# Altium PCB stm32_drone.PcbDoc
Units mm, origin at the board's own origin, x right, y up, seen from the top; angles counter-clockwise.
Board outline 76 x 62 mm, 4 copper layers (Top Layer, Int1 (GND), Int2 (PWR), Bottom Layer), stack 1.564 mm thick; 44 components, 39 nets, 236 pads, 228 vias.
Unrouted connection lines stored in the file: 6.

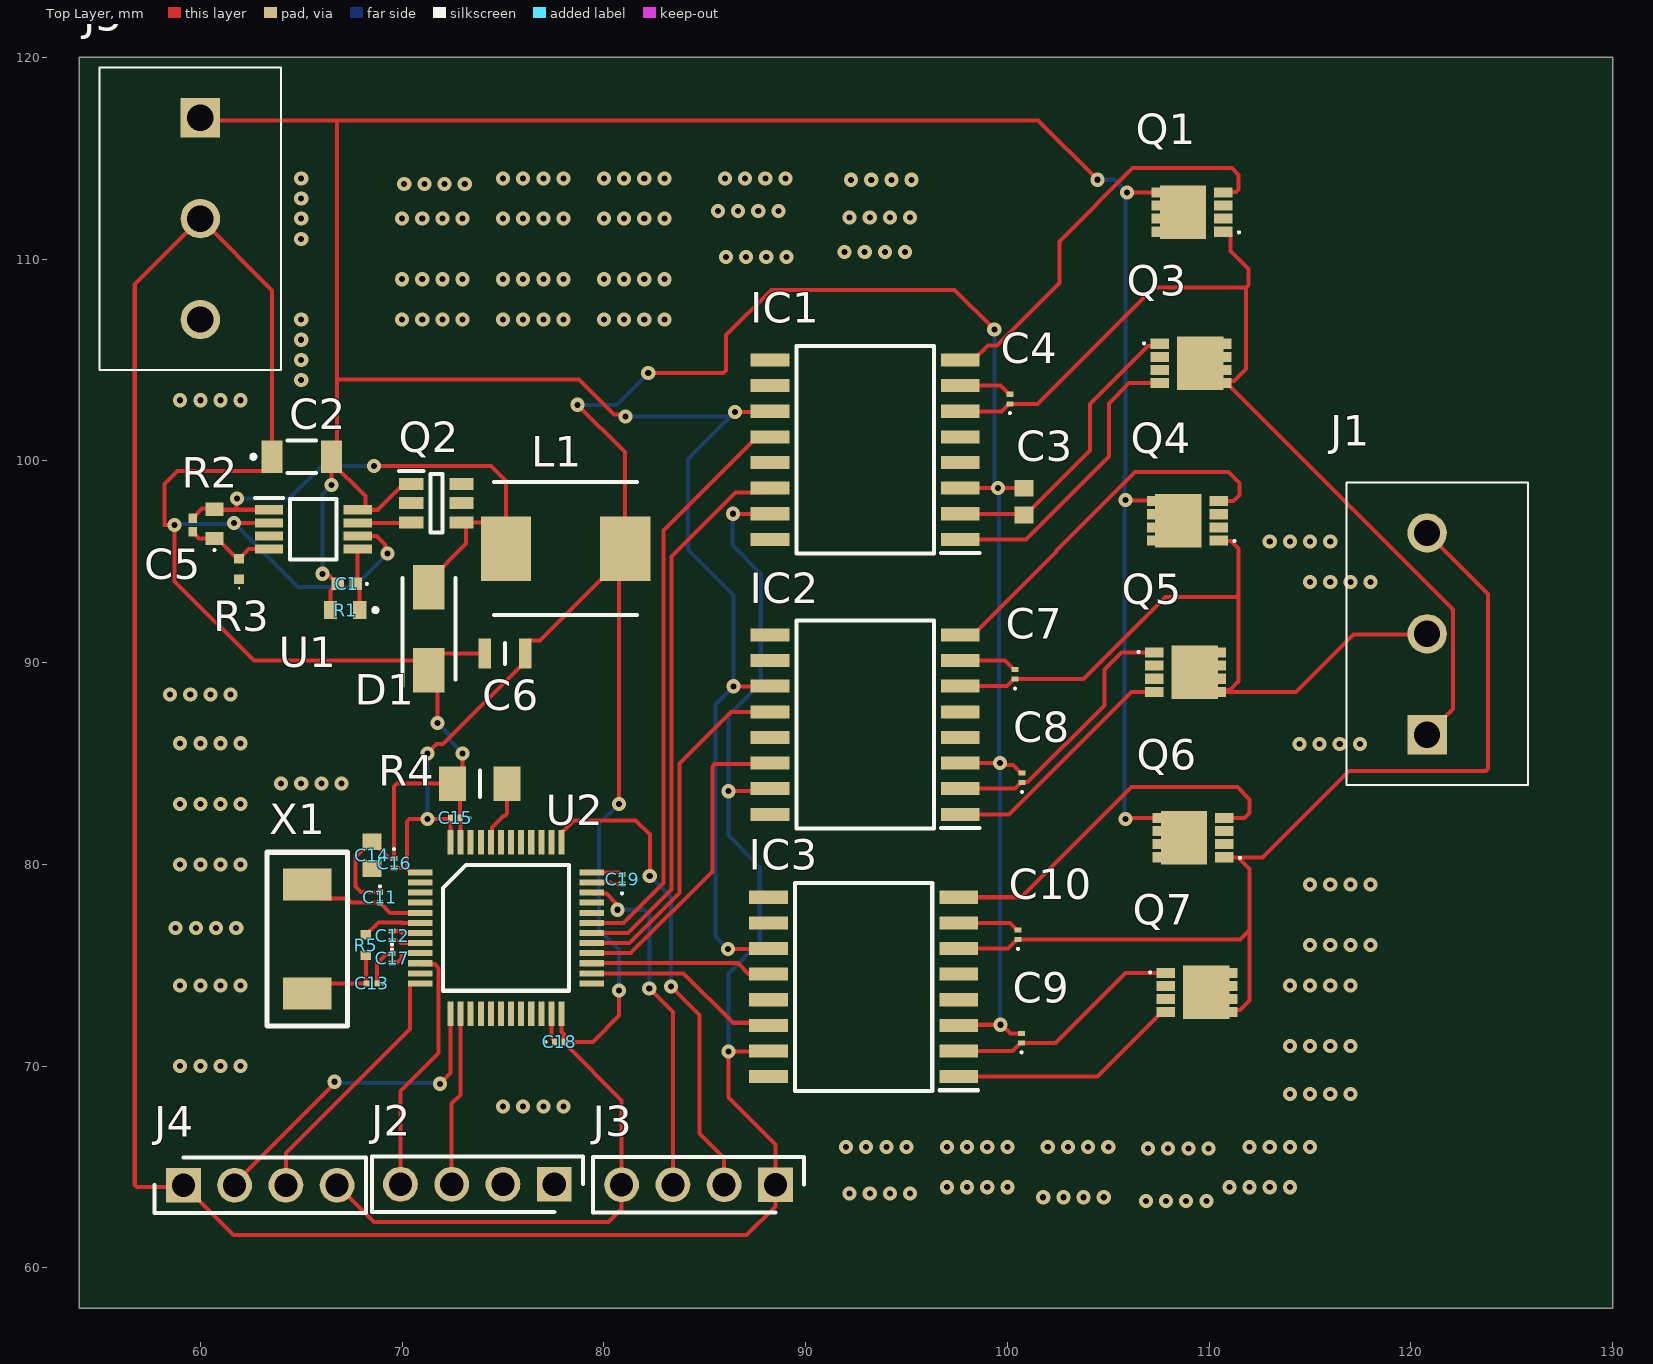
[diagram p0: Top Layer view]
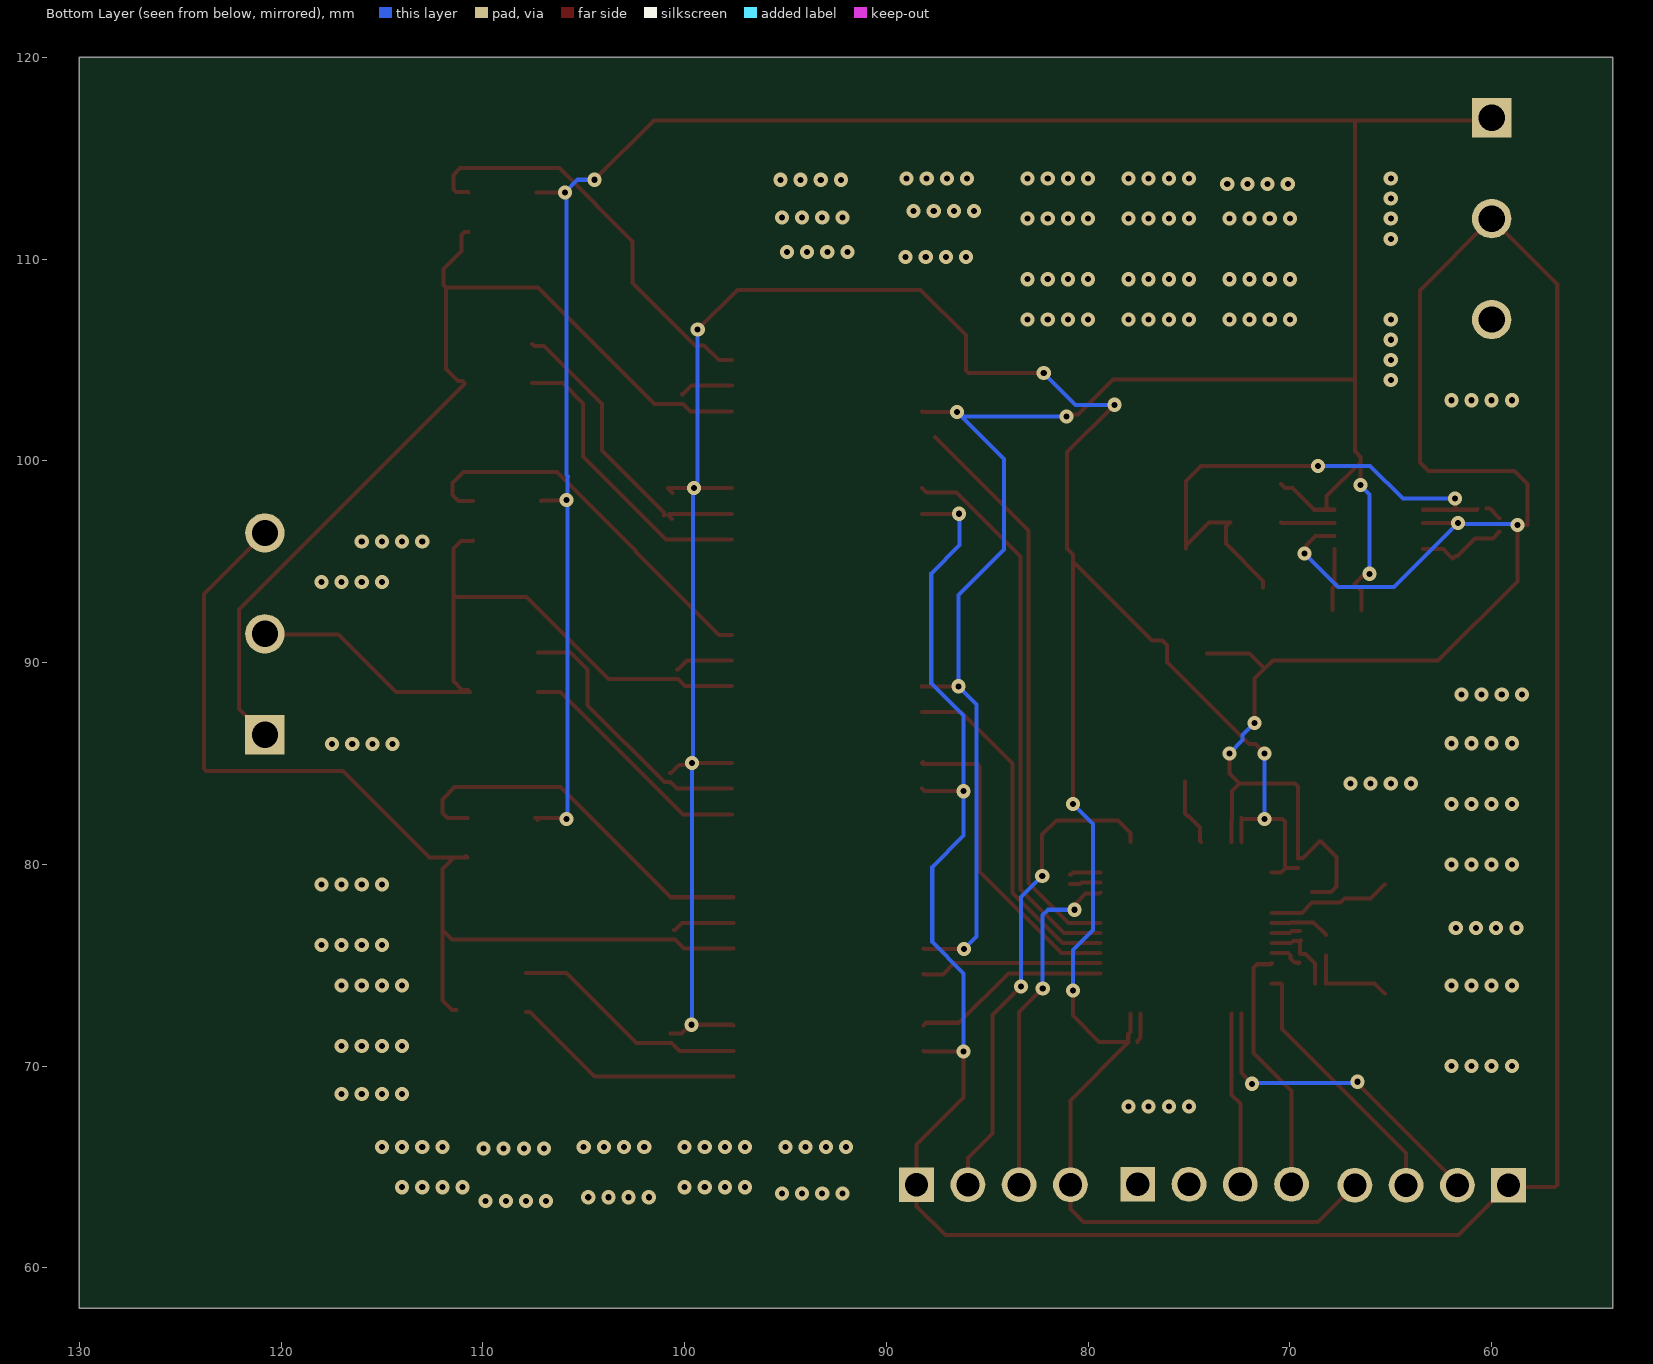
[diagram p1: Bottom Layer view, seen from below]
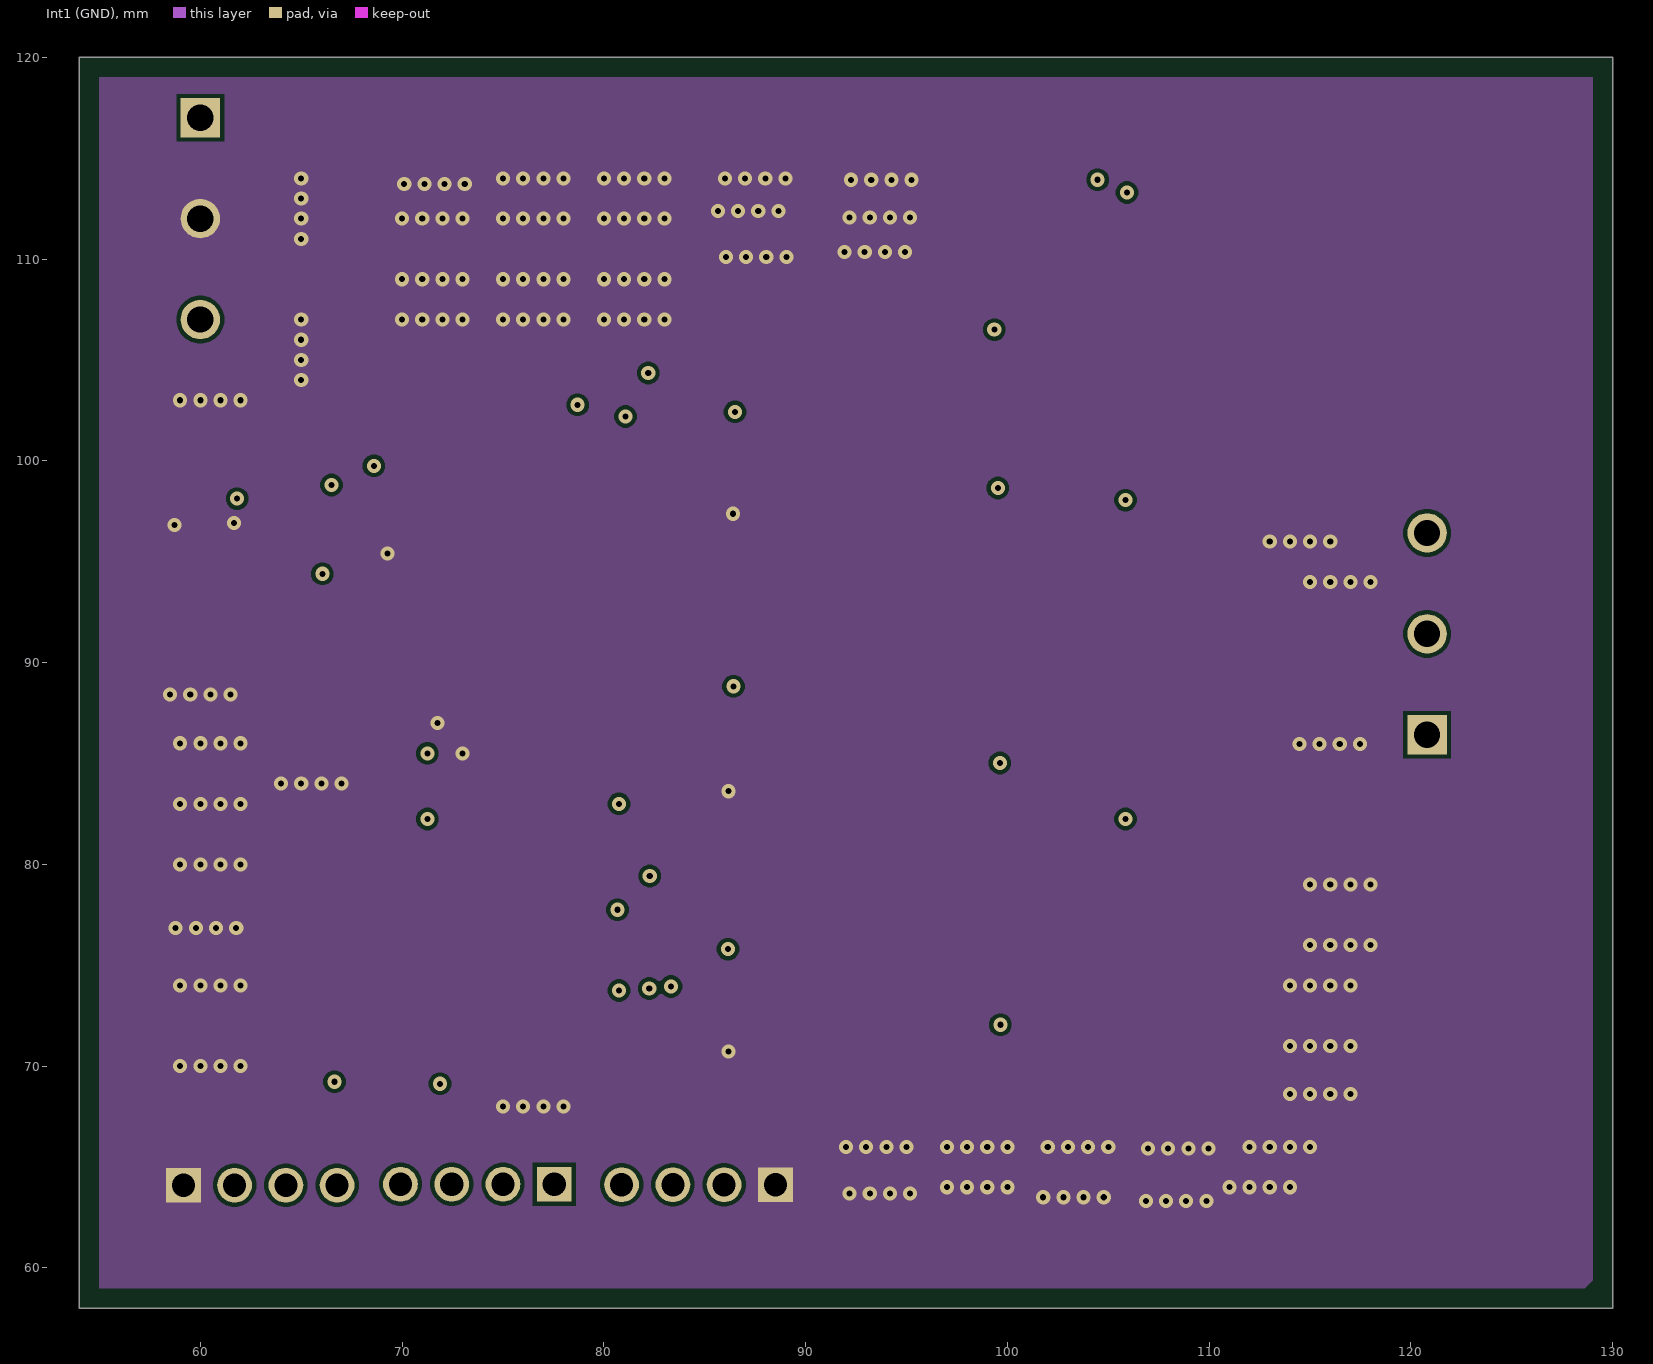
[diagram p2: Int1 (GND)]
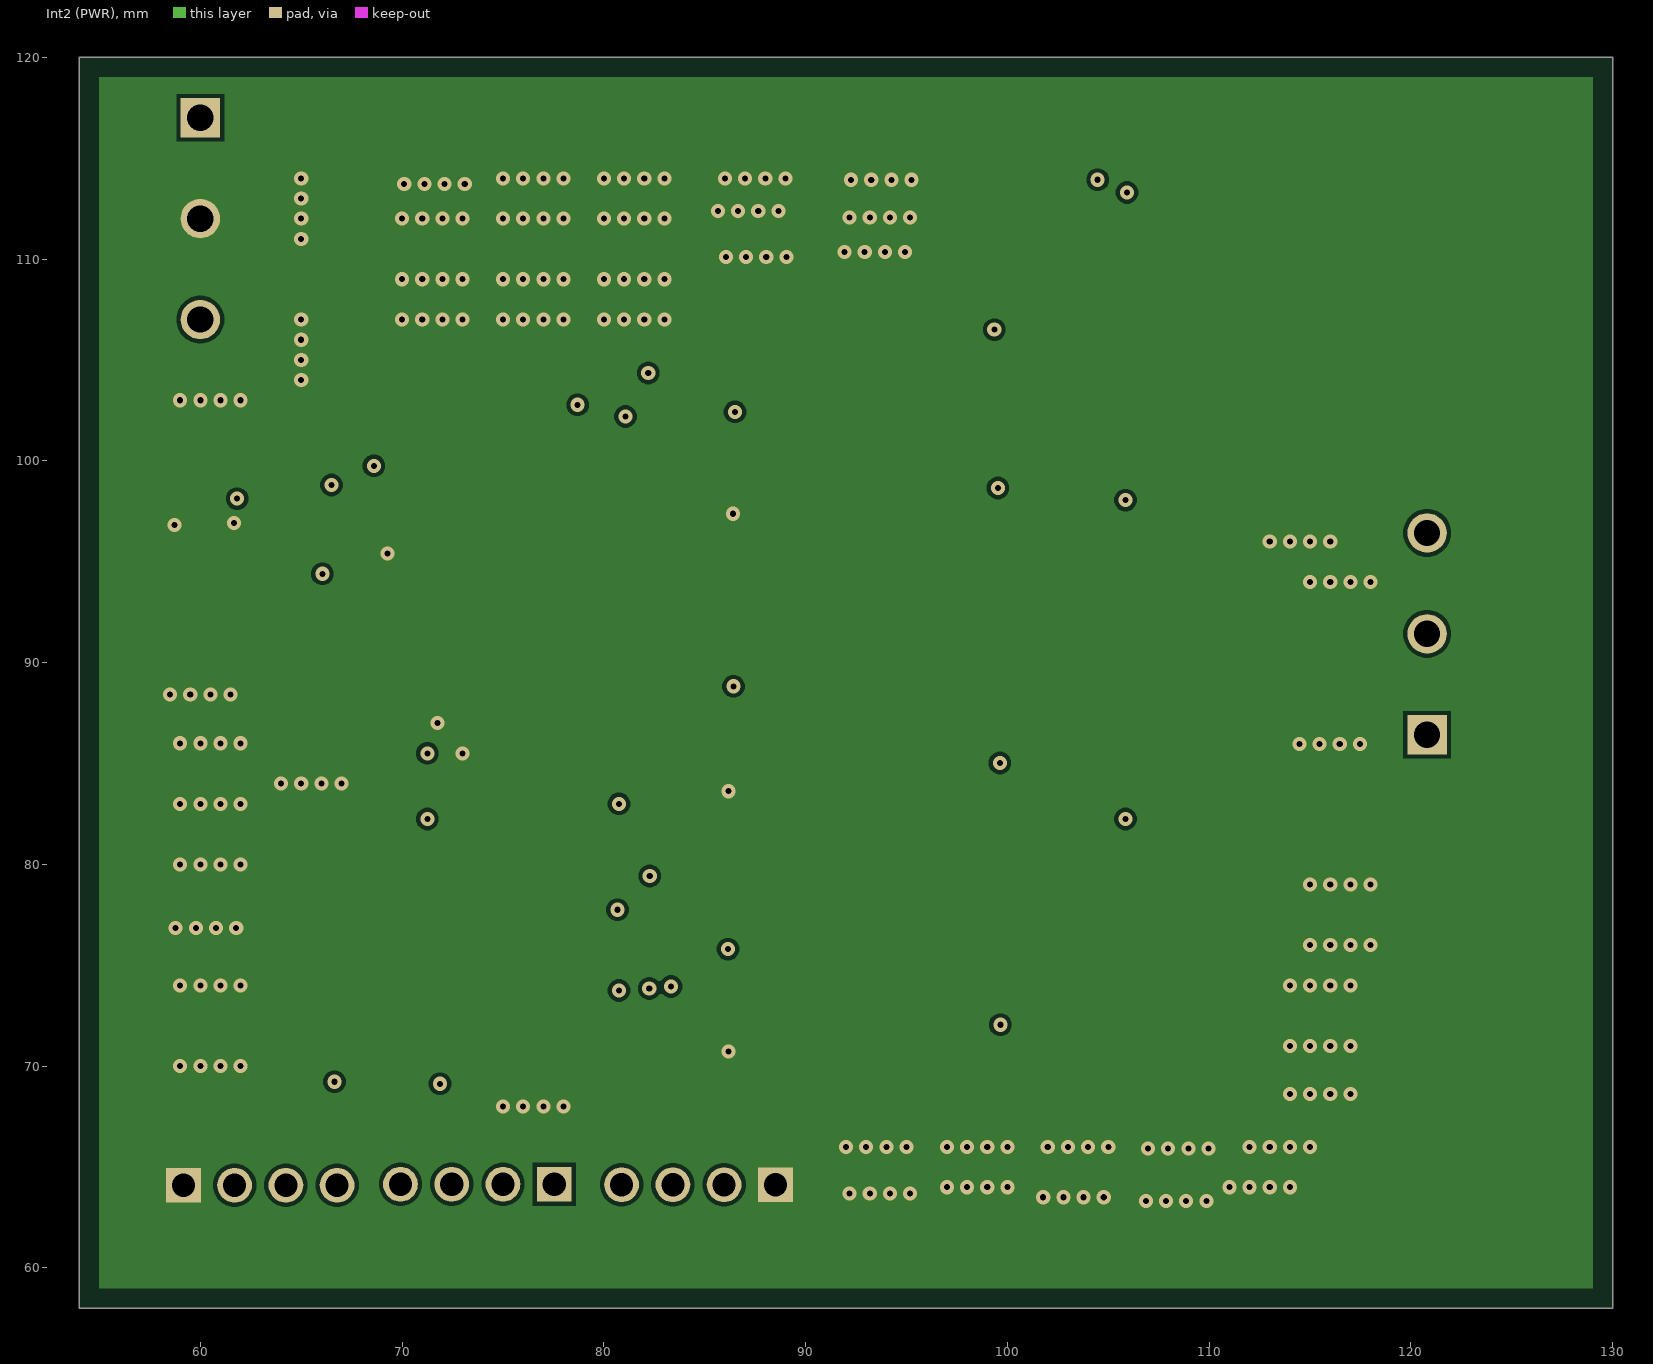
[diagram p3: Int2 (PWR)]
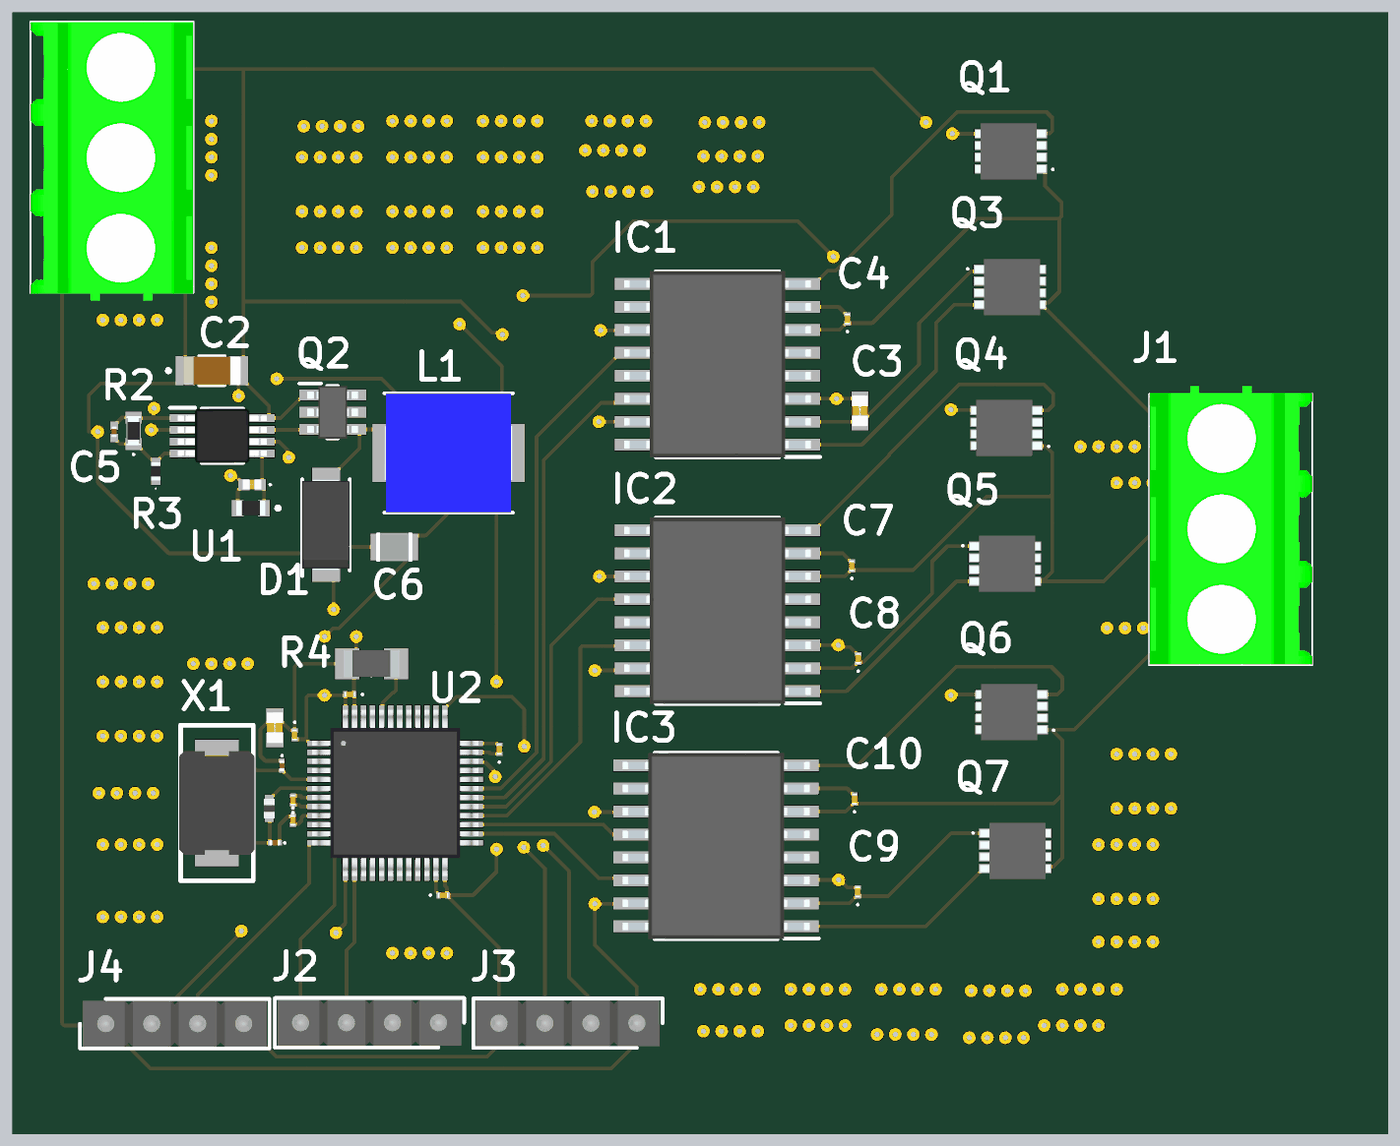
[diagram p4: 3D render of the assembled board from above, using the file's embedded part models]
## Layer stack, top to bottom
Top Solder: solder mask 0.0305, SM-001, Dk 3.8
Top Layer: signal copper 0.035
Dielectric 1: prepreg 0.0994, PP-023, Dk 4.4
Int1 (GND): signal copper 0.0152
Dielectric 3: core 1.265, Core-039, Dk 4.6
Int2 (PWR): signal copper 0.0152
Dielectric 5: prepreg 0.0994, PP-023, Dk 4.4
Bottom Layer: signal copper 0.035
Bottom Solder: solder mask 0.0305, SM-001, Dk 3.8

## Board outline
54,58 54,120 130,120 130,58

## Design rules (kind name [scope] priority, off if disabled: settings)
Clearance [All] p1: gap=0.2 ignorepadtopadclearanceinfootprint=FALSE
PolygonConnect [All] p1: connectstyle=Direct reliefconductorwidth=0.254 reliefentries=4 polygonreliefangle="90 Angle" airgapwidth=0.254
RoutingVias [All] p1: holewidth=0.5 width=0.7 viastyle="Through Hole" minholewidth=0.25 minwidth=0.55 maxholewidth=0.4 maxwidth=0.9
SolderMaskExpansion [All] p1: expansion=0.038 istentingtop=FALSE
SupplyNets "Schematic Supply Nets_1" [InNet('VDD')] p1: voltage=0.000
SupplyNets "Schematic Supply Nets_2" [InNet('3v3')] p2: voltage=0.000
SupplyNets "Schematic Supply Nets" [InNet('GND')] p3: voltage=0.000
UnRoutedNet [All] p1: checkbadconnections=TRUE
Width [All] p1: maxlimit=1 minlimit=0.16 preferedwidth=0.2
29 further rules are at their usual default settings.

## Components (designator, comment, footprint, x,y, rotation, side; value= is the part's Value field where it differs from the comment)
C1 "1nF" C0402C104J4RACTU 67.25,93.9 r180 top
C2 "100uF" GRM31x 65.025,100.2 r0 top
C3 "1uF" CAPC1608X90N 100.825,97.975 r90 top
C4 "1uF" GRM033D70J224ME01D 100.125,103.062 r90 top
C5 "100pF" CAPC0603X33N 59.625,96.82 r90 top
C6 "22uF" CAPC2012X145N 75.1,90.45 r0 top
C7 "1uF" GRM033D70J224ME01D 100.375,89.413 r90 top
C8 "1uF" GRM033D70J224ME01D 100.725,84.287 r90 top
C9 "1uF" GRM033D70J224ME01D 100.7,71.387 r90 top
C10 "1uF" GRM033D70J224ME01D 100.525,76.513 r90 top
C11 "2pF" GJM033 68.9,78.363 r270 top
C12 "100nF" GRM033D70J224ME01D 69.5,76.463 r90 top
C13 "2pF" GJM033 68.5,74.1 r180 top
C14 "1uF" CAPC1608X90N 68.5,80.46 r270 top
C15 "100nF" GRM033D70J224ME01D 72.637,82.3 r180 top
C16 "100nF" GRM033D70J224ME01D 69.6,80.063 r270 top
C17 "100nF" GRM033D70J224ME01D 69.5,75.337 r270 top
C18 "100nF" GRM033D70J224ME01D 77.8,71.2 r0 top
C19 "100nF" GRM033D70J224ME01D 80.9,79.263 r90 top
D1 "1A 40V" DIOM5026X262N 71.325,91.675 r90 top
IC1 "IR2110STRPBF" SOIC127P1032X265-16N 92.95,100.55 r180 top
IC2 "IR2110STRPBF" SOIC127P1032X265-16N 92.95,86.925 r180 top
IC3 "IR2110STRPBF" SOIC127P1032X265-16N 92.875,73.925 r180 top
J1 "1935174" 1935174 120.8,86.425 r90 top
J2 "61300411121" HDRV4W95P0X254_1X4_1016X254X854P 77.54,64.15 r180 top
J3 "61300411121" HDRV4W95P0X254_1X4_1016X254X854P 88.5,64.125 r180 top
J4 "61300411121" HDRV4W95P0X254_1X4_1016X254X854P 59.16,64.1 r0 top
J5 "1935174" 1935174 60,117 r270 top
L1 "22uH" INDPM7166X300N 78.1,95.65 r0 top
Q1 "XPN6R706NC,L1XHQ" XPN6R706NCL1XHQ 109.025,112.325 r90 top
Q2 "FDC5614P" SOT95P280X110-6N 71.7,97.9 r0 top
Q3 "XPN6R706NC,L1XHQ" XPN6R706NCL1XHQ 109.225,104.825 r270 top
Q4 "XPN6R706NC,L1XHQ" XPN6R706NCL1XHQ 108.8,97.025 r90 top
Q5 "XPN6R706NC,L1XHQ" XPN6R706NCL1XHQ 108.95,89.525 r270 top
Q6 "XPN6R706NC,L1XHQ" XPN6R706NCL1XHQ 109.075,81.325 r90 top
Q7 "XPN6R706NC,L1XHQ" XPN6R706NCL1XHQ 109.525,73.65 r270 top
R1 "240k" ERJ3EKF1000V 67.175,92.6 r180 top value=240kR
R2 "33k" ERA3AEB101V 60.7,96.875 r90 top value=33kR
R3 "20k" ERJ2RKD1004X 61.925,94.638 r90 top value=20kR
R4 "10k" RESC3115X60N 73.85,84 r0 top value=10kR
R5 "500" ERA2AED122X 68.2,76 r90 top value=499R
U1 "LM3485MMX/NOPB" SOP65P490X110-8N 65.6,96.6 r0 top
U2 "STMF103C8T6_LQFP48" STM32F103C8T6_LQFP48 75.15,76.85 r0 top
X1 "8Mhz" "8Mhz Crystal" 65.3,76.3 r90 top

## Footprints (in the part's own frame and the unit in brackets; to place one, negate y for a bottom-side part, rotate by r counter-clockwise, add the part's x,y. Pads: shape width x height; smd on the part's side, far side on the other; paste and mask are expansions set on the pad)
"8Mhz Crystal" [mm]
  rect 1.6x2.4 smd: 1(-2.7,0) 2(2.7,0)
  silkscreen extent -4.3,-2 4.3,2, body extent -2.86,-2.09 2.86,2.09, height 1.09
1935174 [mm]
  rect 1.95x1.95 hole 1.3: 1(0,0)
  round 1.95 hole 1.3: 2(5,0) 3(10,0)
  silkscreen extent -2.5,-5 12.5,4, body extent -2.47,-5 12.93,4, height 11.63
C0402C104J4RACTU [mm]
  rect 0.62x0.62 smd: 1(-0.45,0) 2(0.45,0)
  silkscreen extent -1.05,-0.05 -0.95,0.05, body extent -0.52,-0.28 0.53,0.27, height 0.55
CAPC0603X33N [mm]
  rect 0.46x0.42 smd: 1(-0.33,0) 2(0.33,0)
  body extent -0.3,-0.15 0.3,0.15, height 0.33
CAPC1608X90N [mm]
  rect 0.83x0.94 smd: 1(-0.66,0) 2(0.66,0)
  body extent -0.85,-0.45 0.85,0.45, height 0.9
CAPC2012X145N [mm]
  rect 0.62x1.47 smd: 1(-1,0) 2(1,0)
  silkscreen extent 0,-0.53 0,0.53, body extent -1,-0.8 1,0.8, height 1.25
DIOM5026X262N [mm]
  rect 2.2x1.55 smd: 1(-2.05,0) 2(2.05,0)
  silkscreen extent -2.83,-1.31 2.52,1.31, body extent -2.52,-1.31 2.52,1.31, height 2.62
ERA2AED122X [mm]
  rect 0.475x0.5 smd: 1(-0.512,0) 2(0.512,0)
  body extent -0.55,-0.31 0.55,0.31, height 0.41
ERA3AEB101V [mm]
  rect 0.65x0.9 smd: 1(-0.725,0) 2(0.725,0)
  silkscreen extent -1.35,-0.05 -1.25,0.05, body extent -0.8,-0.4 0.8,0.4, height 0.45
ERJ2RKD1004X [mm]
  rect 0.475x0.5 smd: 1(-0.512,0) 2(0.512,0)
  silkscreen extent -0.97,-0.03 -0.93,0.03, body extent -0.5,-0.25 0.5,0.25, height 0.35
ERJ3EKF1000V [mm]
  rect 0.65x0.9 smd: 1(-0.725,0) 2(0.725,0)
  silkscreen extent -1.6,-0.1 -1.4,0.1, body extent -0.8,-0.4 0.8,0.4, height 0.45
GJM033 [mm]
  rect 0.275x0.3 smd: 1(-0.263,0) 2(0.263,0)
  silkscreen extent -0.6,-0.05 -0.5,0.05, body extent -0.3,-0.15 0.3,0.15, height 0.33
GRM31x [mm]
  rect 1.05x1.6 smd: 1(-1.475,0) 2(1.475,0)
  silkscreen extent -2.5,-0.8 0.7,0.8, body extent -1.6,-0.8 1.6,0.8, height 1
GRM033D70J224ME01D [mm]
  rect 0.25x0.35 smd: 1(-0.237,0) 2(0.237,0)
  silkscreen extent -0.75,-0.05 -0.65,0.05, body extent -0.3,-0.15 0.3,0.15, height 0.3
HDRV4W95P0X254_1X4_1016X254X854P [mm]
  rect 1.725x1.725 hole 1.15: 1(0,0)
  round 1.725 hole 1.15: 2(2.54,0) 3(5.08,0) 4(7.62,0)
  silkscreen extent -1.42,-1.37 9.04,1.37, body extent -1.27,-1.27 8.89,1.27, height 8.54
INDPM7166X300N [mm]
  rect 2.5x3.2 smd: 1(-2.95,0) 2(2.95,0)
  silkscreen extent -3.55,-3.3 3.55,3.3, body extent -3.55,-3.3 3.55,3.3, height 3
RESC3115X60N [mm]
  rect 1.35x1.7 smd: 1(-1.35,0) 2(1.35,0)
  silkscreen extent 0,-0.65 0,0.65, body extent -1.55,-0.75 1.55,0.75, height 0.5
SOIC127P1032X265-16N [mm]
  rect 1.925x0.65 smd: 1(-4.712,4.445) 2(-4.712,3.175) 3(-4.712,1.905) 4(-4.712,0.635) 5(-4.712,-0.635) 6(-4.712,-1.905) 7(-4.712,-3.175) 8(-4.712,-4.445) 9(4.712,-4.445) 10(4.712,-3.175) 11(4.712,-1.905) 12(4.712,-0.635) 13(4.712,0.635) 14(4.712,1.905) 15(4.712,3.175) 16(4.712,4.445)
  silkscreen extent -5.68,-5.15 3.4,5.15, body extent -5.16,-5.15 5.16,5.15, height 2.65
SOP65P490X110-8N [mm]
  rect 1.4x0.45 smd: 1(-2.2,0.975) 2(-2.2,0.325) 3(-2.2,-0.325) 4(-2.2,-0.975) 5(2.2,-0.975) 6(2.2,-0.325) 7(2.2,0.325) 8(2.2,0.975)
  silkscreen extent -2.9,-1.5 1.15,1.55, body extent -2.45,-1.5 2.45,1.5, height 1.1
SOT95P280X110-6N [mm]
  rect 1.2x0.6 smd: 1(-1.25,0.95) 2(-1.25,0) 3(-1.25,-0.95) 4(1.25,-0.95) 5(1.25,0) 6(1.25,0.95)
  silkscreen extent -1.85,-1.45 0.3,1.6, body extent -1.4,-1.45 1.4,1.45, height 1.1
STM32F103C8T6_LQFP48 [mm]
  rect 1.2x0.3 smd mask+0.05: 1(-4.25,2.75) 2(-4.25,2.25) 3(-4.25,1.75) 4(-4.25,1.25) 5(-4.25,0.75) 6(-4.25,0.25) 7(-4.25,-0.25) 8(-4.25,-0.75) 9(-4.25,-1.25) 10(-4.25,-1.75) 11(-4.25,-2.25) 12(-4.25,-2.75) 25(4.25,-2.75) 26(4.25,-2.25) 27(4.25,-1.75) 28(4.25,-1.25) 29(4.25,-0.75) 30(4.25,-0.25) 31(4.25,0.25) 32(4.25,0.75) 33(4.25,1.25) 34(4.25,1.75) 35(4.25,2.25) 36(4.25,2.75)
  rect 0.3x1.2 smd mask+0.05: 13(-2.75,-4.25) 14(-2.25,-4.25) 15(-1.75,-4.25) 16(-1.25,-4.25) 17(-0.75,-4.25) 18(-0.25,-4.25) 19(0.25,-4.25) 20(0.75,-4.25) 21(1.25,-4.25) 22(1.75,-4.25) 23(2.25,-4.25) 24(2.75,-4.25) 37(2.75,4.25) 38(2.25,4.25) 39(1.75,4.25) 40(1.25,4.25) 41(0.75,4.25) 42(0.25,4.25) 43(-0.25,4.25) 44(-0.75,4.25) 45(-1.25,4.25) 46(-1.75,4.25) 47(-2.25,4.25) 48(-2.75,4.25)
  silkscreen extent -3.11,-3.11 3.11,3.11, body extent -4.6,-4.6 4.6,4.6, height 1.6
XPN6R706NCL1XHQ [mm]
  rect 0.5x0.9 smd: 1(-0.975,-1.675) 2(-0.325,-1.675) 3(0.325,-1.675) 4(0.975,-1.675)
  rect 0.5x0.4 smd: 5(0.975,1.675) 6(0.325,1.675) 7(-0.325,1.675) 8(-0.975,1.675)
  rect 2.65x2.3 smd: 9(0,0.325)
  silkscreen extent -1.05,-2.5 -0.95,-2.4, body extent -1.55,-2.07 1.55,1.84, height 1

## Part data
C1: library part C0402C102J5GECTU, "Ceramic Capacitor, Multilayer, Ceramic, 50V, 5% +Tol, 5% -Tol, C0G, -/+30ppm/Cel TC, 0.001uF, Surface Mount, 0402", Capacitor Type=Ceramic, Manufacturer=KEMET, Supplier Part Number=399-C0402C102J5GECTUCT-ND
C2: library part GRM31CR60J107MEA8K, "Ceramic Capacitor, Multilayer, Ceramic, 6.3V, 20% +Tol, 20% -Tol, X5R, 15% TC, 100uF, Surface Mount, 1206", Manufacturer=Murata, Supplier Part Number=490-GRM31CR60J107MEA8KCT-ND
C3 C14: library part CC0603KRX5R8BB105, "Ceramic Capacitor, Multilayer, Ceramic, 25V, 10% +Tol, 10% -Tol, X5R, 15% TC, 1uF, Surface Mount, 0603", Capacitor Type=Ceramic, Case/Package=0603, Manufacturer=Yageo, Max Operating Temperature=85°C, Min Operating Temperature=-55°C, Package Shape=Rectangular, Package Style=SMTMeter, Rated DC Voltage (URdc)=25V, Supplier Part Number=311-1445-1-ND, Temperature Characteristics Code=X5R, Tolerance  (fill in as +-)=10%
C4 C7 C8 C9 C10: library part GRM033R60J105MEA2D, "Ceramic Capacitor, Multilayer, Ceramic, 6.3V, 20% +Tol, 20% -Tol, X5R, 15% TC, 1uF, Surface Mount, 0201", Capacitor Type=Ceramic, Case/Package=0201, Manufacturer=Murata, Max Operating Temperature=85°C, Min Operating Temperature=-55°C, Package Shape=Rectangular, Rated DC Voltage (URdc)=6.3V, Supplier Part Number=490-7229-1-ND, Temperature Characteristics Code=X5R, Tolerance  (fill in as +-)=20%
C5: library part GRM0335C1H101JA01D, "Ceramic Capacitor, Multilayer, Ceramic, 50V, 5% +Tol, 5% -Tol, C0G, 30ppm/Cel TC, 0.0001uF, Surface Mount, 0201", Capacitor Type=Ceramic, Case/Package=0201, Manufacturer=Murata, Max Operating Temperature=125°C, Min Operating Temperature=-55°C, Package Shape=Rectangular, Package Style=SMTMeter, Rated DC Voltage (URdc)=50V, Supplier Part Number=490-6113-1-ND, Temperature Characteristics Code=C0G, Tolerance  (fill in as +-)=5%
C6: library part C2012X5R1V226M125AC, "Ceramic Capacitor, Multilayer, Ceramic, 35V, 20% +Tol, 20% -Tol, X5R, 15% TC, 22uF, Surface Mount, 0805", Capacitor Type=Ceramic, Case/Package=0805, Manufacturer=TDK, Max Operating Temperature=85°C, Min Operating Temperature=-55°C, Package Shape=Rectangular, Package Style=SMTMeter, Rated DC Voltage (URdc)=35V, Supplier Part Number=445-14428-1-ND, Temperature Characteristics Code=X5R, Tolerance  (fill in as +-)=20%
C11 C13: library part GJM0335C1E2R0BB01D, "Ceramic Capacitor, Multilayer, Ceramic, 25V, 5% +Tol, 5% -Tol, C0G, 30ppm/Cel TC, 0.000002uF, Surface Mount, 0201", Capacitor Type=Ceramic, Case/Package=0201, Manufacturer=Murata, Max Operating Temperature=125°C, Min Operating Temperature=-55°C, Package Shape=Rectangular, Package Style=SMTMeter, Rated DC Voltage (URdc)=25V, Supplier Part Number=490-11178-1-ND, Temperature Characteristics Code=C0G, Tolerance  (fill in as +-)=5%
C12 C15 C16 C17 C18 C19: library part GRM033C80J104KE15D, "Ceramic Capacitor, Multilayer, Ceramic, 6.3V, 10% +Tol, 10% -Tol, X6S, 22% TC, 0.1uF, Surface Mount, 0201", Capacitor Type=Ceramic, Case/Package=0201, Manufacturer=Murata, Max Operating Temperature=105°C, Min Operating Temperature=-55°C, Package Shape=Rectangular, Rated DC Voltage (URdc)=6.3V, Supplier Part Number=490-10390-1-ND, Temperature Characteristics Code=X6S, Tolerance  (fill in as +-)=10%
D1: library part SS14, "Rectifier Diode, Schottky, 1 Phase, 1 Element, 1A, 40V V(RRM), Silicon, DO-214AC", Forward Voltage=500mV, Manufacturer="ON Semiconductor / Fairchild", Max Operating Temperature=125°C, Max Output current=1A, Max Power Dissipation=1.1W, Min Operating Temperature=-65°C, Non-rep Pk Forward Current-Max=30A, Package Body Material=Plastic, Package Shape=Rectangular, Package Style="SMALL OUTLINEMeter", Rep Pk Reverse Voltage-Max=40V, Supplier Part Number=SS14CT-ND
IC1 IC2 IC3: "Half Bridge Based MOSFET Driver, 2.5A, CMOS, PDSO16", Case/Package=SOP, Manufacturer=Infineon, Max Operating Temperature=125°C, Max Supply Voltage=20V, Min Operating Temperature=-40°C, Min Supply Voltage=3.3V, Nominal Supply Voltage=15V, Output Peak Current Limit-Nom=2.5A, Package Body Material=Plastic, Package Equivalence Code=SOP16,.4, Package Shape=Rectangular, Package Style="SMALL OUTLINEMeter", Peak Reflow Temperature (Cel)=260°C, Supplier Part Number=IR2110SPBFTR-ND, Supply Voltage1-Max=520V, Supply Voltage1-Min=6V, Temperature Grade=AUTOMOTIVE, Time @ Peak Reflow Temperature-Max (s)=30s
J1 J5: "Barrier Strip Terminal Block, 17.5A, 1.5mm2, 1 Row(s), 1 Deck(s)", Current Rating=17.5A, Manufacturer="Phoenix Contact", Supplier Part Number=277-1578-ND, Voltage Rating=250V
L1: library part ECS-MPIL0630-220MC, "General Purpose Inductor, 22uH, 20%, 1 Element, Ferrite-Core, SMD, 2826", Manufacturer="ECS International", Supplier Part Number=XC2409CT-ND
Q1 Q3 Q4 Q5 Q6 Q7: "Mosfet N-ch 60V 40A 8TSON", Manufacturer=Toshiba, Supplier Part Number=264-XPN6R706NCL1XHQCT-ND
Q2: "Small Signal Field-Effect Transistor, 3A I(D), 60V, 1-Element, P-Channel, Silicon, Metal-oxide Semiconductor FET", Drain Current-Max (Abs) (ID)=3A, Drain-source On Resistance-Max=105mR, DS Breakdown Voltage-Min=60V, Manufacturer="ON Semiconductor / Fairchild", Max Operating Temperature=150°C, Operating Mode="ENHANCEMENT MODE", Package Body Material=Plastic, Package Shape=Rectangular, Package Style="SMALL OUTLINEMeter", Power Dissipation-Max (Abs)=1.6W, Supplier Part Number=FDC5614PCT-ND
R1: library part ERJ-3GEYJ244V, "Fixed Resistor, Metal Glaze/thick Film, 0.1W, 240000ohm, 75V, 5% +/-Tol, 200ppm/Cel, Surface Mount, 0603", Case/Package=0603, Manufacturer=Panasonic, Max Operating Temperature=155°C, Min Operating Temperature=-55°C, Package Height=0.45mm, Package Length=1.6mm, Package Shape=Rectangular, Package Width=0.8mm, Power=100mW, Rated Temperature=70°C, Resistor Type="FIXED RESISTOR", Supplier Part Number=P240KGCT-ND, Temperature Coefficient (ppm/Cel)=200, Tolerance=5%, Working Voltage=75V
R2: library part ERA-3AEB333V, "Fixed Resistor, Thin Film, 0.1W, 33000ohm, 75V, 0.1% +/-Tol, 25ppm/Cel, Surface Mount, 0603", Case/Package=0603, Manufacturer=Panasonic, Max Operating Temperature=155°C, Min Operating Temperature=-55°C, Package Height=0.45mm, Package Length=1.6mm, Package Width=0.8mm, Power=100mW, Rated Temperature=85°C, Resistor Type="FIXED RESISTOR", Supplier Part Number=P33KDBCT-ND, Temperature Coefficient (ppm/Cel)=25, Tolerance=0.1%, Working Voltage=75V
R3: library part ERJ-2RKF2002X, "Fixed Resistor, Metal Glaze/thick Film, 0.1W, 20000ohm, 50V, 1% +/-Tol, 100ppm/Cel, Surface Mount, 0402", Case/Package=0402, Manufacturer=Panasonic, Max Operating Temperature=155°C, Min Operating Temperature=-55°C, Package Height=0.35mm, Package Length=1mm, Package Shape=Rectangular, Package Width=0.5mm, Power=100mW, Rated Temperature=70°C, Resistor Type="FIXED RESISTOR", Supplier Part Number=P20.0KLCT-ND, Temperature Coefficient (ppm/Cel)=100, Tolerance=1%, Working Voltage=50V
R4: library part RNCP1206FTD10K0, "Fixed Resistor, Thin Film, 0.5W, 10000ohm, 200V, 1% +/-Tol, 100ppm/Cel, Surface Mount, 1206", Case/Package=1206, Manufacturer="Stackpole Electronics", Max Operating Temperature=155°C, Min Operating Temperature=-55°C, Package Height=0.5mm, Package Length=3.1mm, Package Shape=Rectangular, Package Width=1.5mm, Power=500mW, Rated Temperature=70°C, Resistor Type="FIXED RESISTOR", Supplier Part Number=RNCP1206FTD10K0DKR-ND, Temperature Coefficient (ppm/Cel)=100, Tolerance=1%, Working Voltage=200V
R5: library part ERA-2AEB4990X, "Fixed Resistor, Thin Film, 0.063W, 499ohm, 50V, 0.1% +/-Tol, 25ppm/Cel, Surface Mount, 0402", Case/Package=0402, Manufacturer=Panasonic, Max Operating Temperature=155°C, Min Operating Temperature=-55°C, Package Height=0.35mm, Package Length=1mm, Package Width=0.5mm, Power=63mW, Rated Temperature=85°C, Resistor Type="FIXED RESISTOR", Supplier Part Number=P499DCCT-ND, Temperature Coefficient (ppm/Cel)=25, Tolerance=0.1%, Working Voltage=25V
U1: "Switching Controller, Voltage-mode, 0.1A, 1000kHz Switching Freq-Max, PDSO8", Case/Package=TSSOP, Frequency=1MHz, Manufacturer="TI National Semiconductor", Max Operating Temperature=125°C, Max Output current=100mA, Max Supply Voltage=35V, Min Input Voltage=4.5V, Min Operating Temperature=-40°C, Nominal Supply Voltage=12V, Package Body Material=Plastic, Package Equivalence Code=TSSOP8,.19, Package Shape=Square, Package Style="SMALL OUTLINE, THIN PROFILE, SHRINK PITCHMeter", Peak Reflow Temperature (Cel)=260°C, Supplier Part Number=LM3485MMX/NOPBCT-ND, Temperature Grade=AUTOMOTIVE, Time @ Peak Reflow Temperature-Max (s)=40s
U2: library part STM32F103C8T6, "ARM Cortex-M3 STM32 F1 Microcontroller 32-Bit 72MHz 64kB FLASH LQFP48 STM32F103C8T6", Case/Package=LFQFP, Clock Frequency=16MHz, Manufacturer=STMicroelectronics, Max Operating Temperature=105°C, Max Supply Current=50mA, Max Supply Voltage=3.6V, Min Operating Temperature=-40°C, Min Supply Voltage=2V, Nominal Supply Voltage=3.3V, Package Body Material=Plastic, Package Equivalence Code=QFP48,.35SQ,20, Package Shape=Square, Peak Reflow Temperature (Cel)=260°C, Power Supplies=2.5/3.3, Supplier Part Number=497-6063-ND, Temperature Grade=INDUSTRIAL, Time @ Peak Reflow Temperature-Max (s)=30s
X1: library part H130A-8.000-8-2030-TR, "Parallel - Fundamental Quartz Crystal, 8MHz Min, 150MHz Max, 8MHz Nom", Manufacturer="Raltron Electronics", Supplier Part Number=2151-H130A-8.000-8-2030-TRCT-ND

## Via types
v1: diameter 0.7, hole 0.3, Top Layer to Bottom Layer, 228 vias

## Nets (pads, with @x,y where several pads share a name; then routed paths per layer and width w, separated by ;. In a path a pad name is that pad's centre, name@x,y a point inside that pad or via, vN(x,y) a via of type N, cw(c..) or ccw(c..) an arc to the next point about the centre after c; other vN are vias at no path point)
3v3: C3.2 C6.2 C8.2 C9.2 C14.2 C15.2 C16.2 C17.2 C18.2 C19.2 IC1.3 IC2.3 IC3.3 J3.4 J4.4 L1.2 U2.1 U2.9 U2.24 U2.36 U2.48 | length 158.5
  Top Layer w0.2: J4.4 68.605,62.275 80.233,62.275 80.88,62.922 J3.4 80.88,68.307 78.037,71.15 C18.2 ; C17.2@69.575,75.075 69.525,75.125 69.775,75.125 69.975,75.325 69.975,75.483 70.092,75.6 U2.9 ; C16.2 70.224,79.826 ; 70.25,79.834 70.25,82.133 70.367,82.25 v1(71.25,82.25) 72.375,82.25 72.4,82.275 C15.2 U2.48 ; 70.294,79.756 70.45,79.6 U2.1 ; v1(71.25,85.5) 71.71,85.96 72.035,85.96 76.1,90.025 C6.2 76.1,90.875 76.31,91.085 76.835,91.085 L1.2@80.75,95 ; U2.24 77.9,71.7 78.012,71.588 78.012,71.225 C18.2 ; v1(78.7,102.775) 81.05,100.425 L1.2 80.75,95.35 L1.2@80.75,95 ; U2.36 80.75,79.6 80.85,79.5 C19.2 ; v1(80.75,73.75) 80.75,72.5 79.45,71.2 C18.2 ; v1(80.75,83) L1.2@80.75,95 ; v1(82.2,104.35) 85.933,104.35 86.05,104.467 86.05,106.225 88.3,108.475 97.375,108.475 v1(99.35,106.5) ; IC3.3 97.617,72.05 v1(99.65,72.05) 99.717,72.05 100.143,71.624 C9.2 ; IC2.3 97.667,85.025 v1(99.625,85.025) 99.721,84.929 100.27,84.929 100.675,84.524 C8.2 ; IC1.3 97.667,98.65 v1(99.525,98.65) 100.81,98.65 C3.2 C3.2@100.59,98.4
  Bottom Layer w0.2: v1(71.25,82.25) v1(71.25,85.5) ; v1(78.7,102.775) 80.625,102.775 v1(82.2,104.35) ; v1(80.75,73.75) 80.75,75.75 79.75,76.75 79.75,82 v1(80.75,83) ; v1(99.35,106.5) 99.35,98.96 99.525,98.785 v1(99.525,98.65) 99.575,98.6 99.575,85.075 v1(99.625,85.025) 99.637,85.012 99.637,72.063 v1(99.65,72.05)
GH1: IC1.8 Q1.4 | length 20.6
  Top Layer w0.2: IC1.8 98.299,104.995 99.03,105.725 99.495,105.725 102.575,108.806 102.575,110.869 106.206,114.5 111.125,114.5 111.45,114.175 111.45,113.442 111.333,113.325 110.725,113.325 Q1.4
GH2: IC2.8 Q4.4 | length 19.2
  Top Layer w0.2: IC2.8 98.299,91.37 102.428,95.498 102.428,95.547 106.331,99.45 110.95,99.45 111.5,98.9 111.5,98.3 111.2,98 Q4.4
GH3: IC3.8 Q6.4 | length 18.9
  Top Layer w0.2: IC3.8 100.695,78.37 106.15,83.825 111.4,83.825 112,83.225 112,82.55 111.75,82.3 Q6.4
GL1: IC1.1 Q3.4 | length 14.6
  Top Layer w0.2: IC1.1 100.924,96.105 105.025,100.206 105.025,102.85 106.025,103.85 Q3.4
GL2: IC2.1 Q5.4 | length 12.1
  Top Layer w0.2: IC2.1 100.08,82.48 106.15,88.55 Q5.4
GL3: IC3.1 Q7.4 | length 11.6
  Top Layer w0.2: IC3.1 104.455,69.48 107.65,72.675 Q7.4
GND: C2.1 C6.1 C11.1 C12.1 C13.1 C14.1 C15.1 C16.1 C17.1 C18.1 C19.1 D1.1 IC1.15 IC2.15 IC3.15 J3.1 J4.1 J5.2 R4.1 U1.2 U1.6 U2.8 U2.23 U2.35 U2.47 | length 213.6
  Top Layer w0.2: v1(61.675,96.925) U1.2 ; U1.6 68.725,96.275 69.179,95.821 69.179,95.496 v1(69.275,95.4) ; C13.1 68.763,75.087 69.225,75.549 69.475,75.549 C17.1 C12.1 ; C11.1 67.974,78.626 67.7,78.9 67.7,80.375 68.445,81.12 C14.1 68.555,81.12 69.35,80.325 69.525,80.325 69.55,80.3 C16.1 69.6,83.85 69.75,84 R4.1 ; C12.1@69.45,76.226 C12.1 ; U2.8 69.934,76.1 69.833,76.201 69.525,76.201 C12.1 ; v1(71.75,87) 71.75,89.2 D1.1 ; U2.47 72.9,82.224 72.874,82.25 C15.1 72.874,83.626 R4.1 ; v1(73,85.5) 73,84.5 R4.1 ; C6.1 72,90.45 71.325,89.775 D1.1 ; U2.23 77.4,71.413 77.563,71.25 C18.1 ; U2.35 80.338,79.1 80.412,79.026 C19.1 ; v1(86.175,83.625) 88.113,83.625 IC2.15 ; v1(86.4,97.375) IC1.15 ; IC3.15 88.138,70.725 v1(86.175,70.725) 86.175,68.445 88.5,66.12 J3.1 88.5,63.05 87.075,61.625 61.635,61.625 J4.1 59.06,64 56.867,64 56.75,64.117 56.75,108.75 J5.2 63.55,108.45 C2.1 63.55,99.925 63.125,99.5 58.875,99.5 58.225,98.85 58.225,96.825 v1(58.725,96.825) 58.725,94.025 62.65,90.1 70.85,90.1 D1.1
  Bottom Layer w0.2: v1(58.725,96.825) 58.775,96.875 61.625,96.875 v1(61.675,96.925) 64.85,93.75 67.625,93.75 v1(69.275,95.4) ; v1(71.75,87) 72.341,86.409 72.341,86.159 v1(73,85.5) ; v1(86.175,70.725) 86.175,74.593 87.725,76.143 87.725,79.875 86.175,81.425 v1(86.175,83.625) 86.175,87.368 87.775,88.968 87.775,94.425 86.375,95.825 86.375,97.35 v1(86.4,97.375)
  other v1: 106.859,63.322 107.859,63.322 108.859,63.322 109.859,63.322 101.773,63.503 102.773,63.503 103.773,63.503 104.773,63.503 92.179,63.683 93.179,63.683 94.179,63.683 95.179,63.683 97,64 98,64 99,64 100,64 111,64 112,64 113,64 114,64 106.967,65.919 107.967,65.919 108.967,65.919 109.967,65.919 92,66 93,66 94,66 95,66 97,66 98,66 99,66 100,66 102,66 103,66 104,66 105,66 112,66 113,66 114,66 115,66 75,68 76,68 77,68 78,68 114.001,68.625 115.001,68.625 116.001,68.625 117.001,68.625 59,70 60,70 61,70 62,70 114,71 115,71 116,71 117,71 59,74 60,74 61,74 62,74 114,74 115,74 116,74 117,74 115,76 116,76 117,76 118,76 58.779,76.848 59.779,76.848 60.779,76.848 61.779,76.848 115,79 116,79 117,79 118,79 59,80 60,80 61,80 62,80 59,83 60,83 61,83 62,83 64,84 65,84 66,84 67,84 114.47,85.974 115.47,85.974 116.47,85.974 117.47,85.974 59,86 60,86 61,86 62,86 58.5,88.425 59.5,88.425 60.5,88.425 61.5,88.425 115,94 116,94 117,94 118,94 113,96 114,96 115,96 116,96 59,103 60,103 61,103 62,103 65,104 65,105 65,106 65,107 70,107 71,107 72,107 73,107 75,107 76,107 77,107 78,107 80,107 81,107 82,107 83,107 70,109 71,109 72,109 73,109 75,109 76,109 77,109 78,109 80,109 81,109 82,109 83,109 86.047,110.104 87.047,110.104 88.047,110.104 89.047,110.104 91.926,110.356 92.926,110.356 93.926,110.356 94.926,110.356 65,111 65,112 70,112 71,112 72,112 73,112 75,112 76,112 77,112 78,112 80,112 81,112 82,112 83,112 92.179,112.052 93.179,112.052 94.179,112.052 95.179,112.052 85.65,112.376 86.65,112.376 87.65,112.376 88.65,112.376 65,113 70.105,113.711 71.105,113.711 72.105,113.711 73.105,113.711 92.251,113.927 93.251,113.927 94.251,113.927 95.251,113.927 65,114 75,114 76,114 77,114 78,114 80,114 81,114 82,114 83,114 86,114 87,114 88,114 89,114
MCU_OSC_IN: C11.2 U2.5 X1.2 | length 6.2
  Top Layer w0.2: X1.2 66,78.3 67.3,78.3 67.5,78.1 C11.2 68.912,78.1 69.413,77.6 U2.5
MCU_OSC_OUT: R5.2 U2.6 | length 3
  Top Layer w0.2: R5.2 68.213,76.512 68.825,77.125 69.975,77.125 70,77.1 U2.6 U2.6@70.875,77.125
MCU_SWCLK: J3.2 U2.37 | length 24.3
  Top Layer w0.2: U2.37 77.9,81.55 78.525,82.175 81.575,82.175 82.275,81.475 v1(82.275,79.425) ; v1(83.325,73.95) 84.75,72.525 84.75,66.65 85.96,65.44 J3.2
  Bottom Layer w0.2: v1(82.275,79.425) 83.325,78.375 v1(83.325,73.95)
MCU_SWDIO: J3.3 U2.34 | length 17.3
  Top Layer w0.2: U2.34 79.45,78.55 80.124,78.55 80.579,78.095 80.579,77.846 v1(80.675,77.75) ; v1(82.25,73.85) 83.42,72.68 J3.3
  Bottom Layer w0.2: v1(80.675,77.75) 82,77.75 82.25,77.5 v1(82.25,73.85)
NetC1_1: C1.1 R1.1 U1.5 | length 3.1
  Top Layer w0.2: U1.5 67.8,94 C1.1 67.9,93.7 R1.1
NetC3_1: C3.1 IC1.2 Q3.1 | length 14.9
  Top Layer w0.2: IC1.2 100.765,97.375 C3.1 C3.1@100.635,97.125 ; C3.1@101.01,97.3 101.01,97.445 104.085,100.52 104.085,102.81 106.976,105.7 107.45,105.7 Q3.1
NetC4_2: C4.2 IC1.7 | length 2.6
  Top Layer w0.2: IC1.7 99.649,103.725 100.075,103.299 C4.2
NetC5_1: C5.1 R3.2 U1.4 | length 4.5
  Top Layer w0.2: C5.1 59.625,96.47 59.945,96.15 60.7,96.15 60.825,96.15 61.688,95.288 61.787,95.288 R3.2 61.937,95.15 62.259,95.471 62.259,95.484 62.4,95.625 U1.4
NetC5_2: C5.2 D1.2 L1.1 Q2.4 R2.2 U1.1 | length 28.5
  Top Layer w0.2: C5.2 59.625,97.17 60.08,97.625 60.25,97.625 ; R2.2 60.725,97.575 61.8,97.575 ; v1(61.825,98.125) 61.8,98.1 61.8,97.575 ; U1.1 61.8,97.575 ; v1(68.6,99.75) 74.4,99.75 75.15,99 L1.1@75.15,95.8 ; D1.2 71.325,94.05 73.175,95.9 73.175,96.75 Q2.4@72.975,96.95 ; Q2.4 Q2.4@72.975,96.95 ; L1.1 L1.1@75.15,95.8 ; Q2.4@72.975,96.95 74,96.95 L1.1@75.15,95.8
  Bottom Layer w0.2: v1(61.825,98.125) 64.4,98.125 66.025,99.75 v1(68.6,99.75)
NetC7_2: C7.2 IC2.7 | length 2.9
  Top Layer w0.2: IC2.7 99.875,90.1 100.325,89.65 C7.2
NetC8_1: C8.1 IC2.2 Q5.1 | length 13.4
  Top Layer w0.2: IC2.2 100.375,83.75 100.675,84.05 C8.1 100.75,84.075 101,84.075 104.8,87.875 104.8,89.65 105.65,90.5 Q5.1
NetC9_1: C9.1 IC3.2 Q7.1 | length 11.9
  Top Layer w0.2: IC3.2 100.25,70.75 100.65,71.15 C9.1 102.387,71.15 105.862,74.625 Q7.1
NetC10_2: C10.2 IC3.7 | length 3.1
  Top Layer w0.2: IC3.7 100.125,77.1 100.475,76.75 C10.2
NetC12_2: C12.2 U2.7 | length 1.4
  Top Layer w0.2: C12.2 69.9,76.7 70,76.6 U2.7
NetC13_2: C13.2 X1.1 | length 4.5
  Top Layer w0.2: X1.1 65.8,74.1 C13.2@68.225,74.1 ; 68.2,75.488 68.219,75.469 68.219,74.106 C13.2@68.225,74.1 ; C13.2 C13.2@68.225,74.1
NetQ2_3: Q2.3 U1.7 | length 2.7
  Top Layer w0.2: U1.7 70.425,96.925 Q2.3
NetR4_2: R4.2 U2.44 | length 3.4
  Top Layer w0.2: U2.44 74.45,81.15 74.45,81.824 75.026,82.4 75.083,82.4 75.2,82.517 R4.2@75.2,84.1
PA4: J2.3 U2.14 | length 8.6
  Top Layer w0.2: J2.3 72.46,68.136 72.9,68.576 U2.14
"PHASE A": C4.1 IC1.6 J1.1 Q1.1 Q3.5 | length 47.9
  Top Layer w0.2: IC1.6 99.705,102.455 100.075,102.825 C4.1 101.5,102.825 107.275,108.6 111.833,108.6 ; Q1.1 110.9,111.35 111.05,111.2 111.05,110.409 111.95,109.509 111.95,108.717 111.833,108.6 ; Q3.5 110.9,103.8 122.075,92.625 122.075,87.7 J1.1 ; Q3.5@111,103.95 111.224,103.95 111.833,104.559 111.833,108.6
"PHASE B": C7.1 IC2.6 J1.2 Q4.1 Q5.5 | length 35.8
  Top Layer w0.2: IC2.6 99.979,88.83 100.325,89.176 C7.1 103.76,89.176 107.834,93.25 111.333,93.25 111.45,93.367 ; Q4.1 110.5,96.025 111.075,96.025 111.45,95.65 111.45,93.367 ; J1.2 120.775,91.4 117.15,91.4 114.3,88.55 Q5.5 110.725,88.65 111.025,88.65 111.45,89.075 111.45,93.367
"PHASE C": C10.1 IC3.6 J1.3 Q6.1 Q7.5 | length 51
  Top Layer w0.2: IC3.6 100.029,75.83 100.475,76.276 C10.1 111.526,76.276 112,76.75 ; Q6.1@110.825,80.425 Q6.1 111.425,80.35 ; Q7.5@111.3,72.775 111.524,72.775 112,73.251 112,76.75 ; J1.3 123.825,93.4 123.825,84.742 123.708,84.625 116.925,84.625 112.65,80.35 111.425,80.35 ; 111.425,80.35 112,79.775 112,76.75
S1: IC1.12 U2.31 | length 28.4
  Top Layer w0.2: U2.31 80.984,77.1 82.958,79.074 82.958,96.542 IC1.12@87.601,101.185
S2: IC1.14 U2.30 | length 27.6
  Top Layer w0.2: U2.30 81.2,76.6 83.358,78.758 83.358,95.252 86.526,98.42 88.013,98.42 IC1.14
S3: IC2.12 U2.29 | length 17.3
  Top Layer w0.2: U2.29 81.266,76.1 83.758,78.592 83.758,85.008 86.31,87.56 IC2.12
S4: IC2.14 U2.28 | length 15.9
  Top Layer w0.2: U2.28 81.331,75.6 85.375,79.644 85.375,84.858 85.492,84.975 88.193,84.975 IC2.14 IC2.14@88.183,85.075
S5: IC3.12 U2.27 | length 9
  Top Layer w0.2: U2.27 86.65,75.1 87.2,74.55 88.153,74.55 IC3.12
S6: IC3.14 U2.26 | length 9.8
  Top Layer w0.2: U2.26 83.95,74.6 86.4,72.15 88.033,72.15 IC3.14
TIM2_PWM: J2.4 U2.10 | length 12.5
  Top Layer w0.2: J2.4 69.92,68.778 71.8,70.658 71.8,74.874 71.624,75.05 70.95,75.05 U2.10
USART2_RX: J4.2 U2.13 | length 16.1
  Top Layer w0.2: J4.2 61.7,64.187 66.65,69.137 v1(66.65,69.225) ; v1(71.875,69.125) 72.4,69.65 U2.13
  Bottom Layer w0.2: v1(66.65,69.225) 66.7,69.175 71.825,69.175 v1(71.875,69.125)
USART2_TX: J4.3 U2.12 | length 13
  Top Layer w0.2: J4.3 64.24,65.69 70.4,71.85 70.4,74.05 70.45,74.1 U2.12
VDD: C1.2 C2.2 IC1.11 IC2.11 IC3.11 J5.1 Q1.5 Q2.1 Q4.5 Q6.5 R1.2 U1.8 | length 169.7
  Top Layer w0.2: J5.1 60.125,116.875 66.775,116.875 ; v1(66.05,94.4) 66.3,94.4 C1.2 66.45,93.55 R1.2 ; v1(66.5,98.8) C2.2@66.5,99.925 ; U1.8 U1.8@68.05,97.575 ; Q2.1 70.25,98.65 69.875,98.65 68.8,97.575 U1.8@68.05,97.575 ; v1(81.075,102.2) 80.979,102.296 80.504,102.296 78.775,104.025 66.8,104.025 66.775,104 ; v1(86.15,75.8) 88.133,75.8 IC3.11 ; v1(86.425,88.825) 88.233,88.825 IC2.11 ; v1(86.5,102.425) 88.208,102.425 IC1.11 ; v1(104.473,113.929) 101.527,116.875 66.775,116.875 ; v1(105.85,82.25) v1@105.875,82.275 ; v1(105.85,98.05) 105.875,98.025 107.1,98.025 Q4.5 ; v1@105.9,113.275 v1(105.925,113.3) Q1.5 ; v1@105.975,82.3 Q6.5 ; Q6.5@107.3,82.2 Q6.5@107.3,82.275 ; C2.2@66.5,99.925 C2.2 66.775,100.475 66.775,104 ; C2.2@66.5,99.925 68.175,98.25 68.175,97.7 U1.8@68.05,97.575 ; 66.775,104 66.775,116.875
  Bottom Layer w0.2: v1(66.05,94.4) 66.05,98.331 66.5,98.781 v1(66.5,98.8) ; v1(81.075,102.2) 86.14,102.2 86.365,102.425 v1(86.5,102.425) 84.175,100.1 84.175,95.602 86.425,93.352 v1(86.425,88.825) 85.525,87.925 85.525,76.425 v1(86.15,75.8) ; v1(104.473,113.929) 105.296,113.929 v1(105.925,113.3) 105.85,113.225 105.85,99.3 105.775,99.225 105.812,99.188 105.812,82.288 v1(105.85,82.25)
pads on no net: IC1.4 IC1.5 IC1.9 IC1.10 IC1.13 IC1.16 IC2.4 IC2.5 IC2.9 IC2.10 IC2.13 IC2.16 IC3.4 IC3.5 IC3.9 IC3.10 IC3.13 IC3.16 J2.1 J2.2 J5.3 Q1.2 Q1.3 Q1.6 Q1.7 Q1.8 Q1.9 Q2.2 Q2.5 Q2.6 Q3.2 Q3.3 Q3.6 Q3.7 Q3.8 Q3.9 Q4.2 Q4.3 Q4.6 Q4.7 Q4.8 Q4.9 Q5.2 Q5.3 Q5.6 Q5.7 Q5.8 Q5.9 Q6.2 Q6.3 Q6.6 Q6.7 Q6.8 Q6.9 Q7.2 Q7.3 Q7.6 Q7.7 Q7.8 Q7.9 R2.1 R3.1 R5.1 U1.3 U2.2 U2.3 U2.4 U2.11 U2.15 U2.16 U2.17 U2.18 U2.19 U2.20 U2.21 U2.22 U2.25 U2.32 U2.33 U2.38 U2.39 U2.40 U2.41 U2.42 U2.43 U2.45 U2.46

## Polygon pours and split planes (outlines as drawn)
GND on Int1 (GND) "GND_L02_P000" (solid, pour order 0): 55,119 129,119 129,59.383 128.617,59 55,59
GND on Int2 (PWR) "GND_L03_P001" (solid, pour order 1): 55,119 129,119 129,59 55,59

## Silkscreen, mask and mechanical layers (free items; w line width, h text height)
Mechanical 1:
  lines w0.191: 54,58 54,120 55,120 130,120 130,58 54,58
